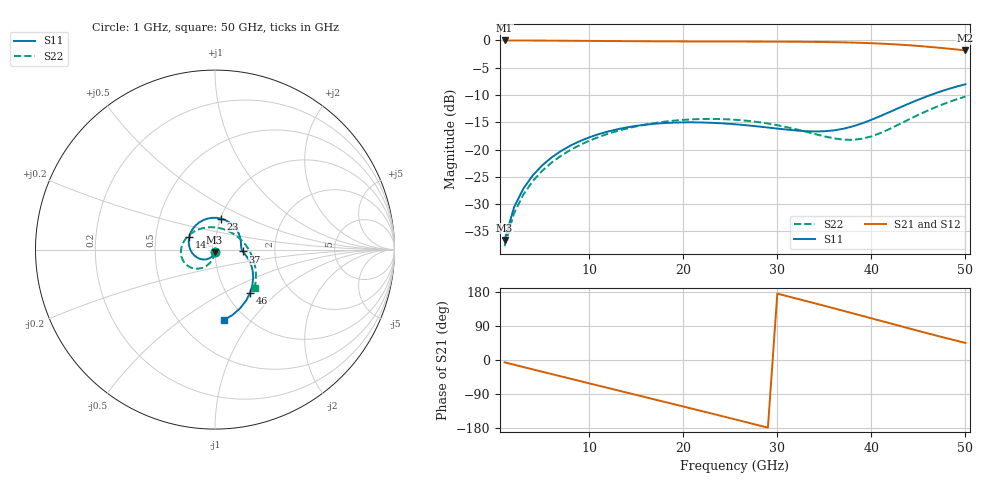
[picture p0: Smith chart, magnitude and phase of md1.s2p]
! Impedora 0.10.0 via model, case md1 (fullwave/cases.json), 2026-11-19
! Differential pair with a microstrip launch: 0.5 mm pads 0.2 mm above the top plane, traces side by side at the 0.8 mm via pitch: with its pads and traces, ports at the far end of each trace, after the 3D port calibration.
! Differential mode only: port 1 and port 2 are the pair at each end (Sdd11, Sdd21), 100 ohm differential.
! Compared with the edge 3D mesh.
# Hz S RI R 100
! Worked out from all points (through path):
!   50 points, 1 GHz to 50 GHz, reference 100 ohm
!   highest |S21| = 0.00 dB at 1 GHz (marker M1); lowest = -1.8 dB at 50 GHz (marker M2)
!   group delay of S21, straight-line fit = 17.5 ps
!   lowest |S11| = -36.6 dB at 1 GHz (marker M3), VSWR 1.03, Z = 99.5 - j2.92 ohm
!   |S11| at or under -10 dB: start of sweep to 46.3 GHz
!   |S22| runs from -37.7 to -10.3 dB; largest |S21 - S12| = 1.6
!   S11 on the Smith chart (normalised r, x): 1 GHz: 1.00, -0.03; 14 GHz: 0.74, +0.11; 23 GHz: 1.01, +0.36; 37 GHz: 1.37, -0.03; 46 GHz: 1.29, -0.68; 50 GHz: 0.79, -0.74
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1e9  -0.00211 -0.0147  0.9941 -0.1077  0.9982 -0.0581  -0.000761 -0.013
2e9  -0.00832 -0.0283  0.9763 -0.2141  0.9929 -0.116  -0.00303 -0.0258
3e9  -0.0183 -0.04  0.947 -0.3178  0.984 -0.1733  -0.00678 -0.0382
4e9  -0.0314 -0.0488  0.9066 -0.4175  0.9717 -0.23  -0.0119 -0.0501
7e9  -0.0818 -0.0523  0.7251 -0.681  0.9148 -0.3933  -0.035 -0.0805
1e10  -0.1282 -0.0176  0.4709 -0.8714  0.8302 -0.5427  -0.0668 -0.1002
1.4e10  -0.1441 0.069  0.0677 -0.9828  0.6812 -0.713  -0.1151 -0.1053
1.6e10  -0.1249 0.1141  -0.1413 -0.9727  0.5939 -0.7837  -0.1384 -0.0981
1.8e10  -0.0893 0.1506  -0.3434 -0.9191  0.4995 -0.844  -0.159 -0.0846
2e10  -0.0422 0.1725  -0.5298 -0.8242  0.3992 -0.8934  -0.1754 -0.0653
2.3e10  0.0347 0.1725  -0.7624 -0.6133  0.2396 -0.9462  -0.189 -0.0274
2.6e10  0.0982 0.1378  -0.9172 -0.3377  0.0718 -0.9719  -0.1855 0.0173
2.8e10  0.1254 0.1038  -0.9677 -0.1309  -0.043 -0.9728  -0.1719 0.048
3e10  0.1398 0.0688  -0.9717 0.0834  -0.1589 -0.9597  -0.1485 0.0769
3.2e10  0.1446 0.0383  -0.9275 0.2948  -0.2741 -0.9317  -0.1151 0.1014
3.4e10  0.1457 0.0152  -0.8356 0.4921  -0.3868 -0.8878  -0.0723 0.1184
3.7e10  0.1547 -0.0102  -0.6167 0.7365  -0.5443 -0.7906  0.00608 0.1232
4e10  0.1817 -0.0458  -0.3241 0.8862  -0.677 -0.657  0.092 0.0947
4.2e10  0.2029 -0.09  -0.1091 0.9199  -0.7445 -0.5512  0.1455 0.0547
4.4e10  0.2128 -0.1562  0.1028 0.8979  -0.7911 -0.437  0.189 -0.000786
4.6e10  0.1961 -0.2395  0.2949 0.8248  -0.8152 -0.3207  0.2176 -0.0678
5e10  0.0474 -0.3939  0.5732 0.5735  -0.8038 -0.1065  0.2214 -0.2112
